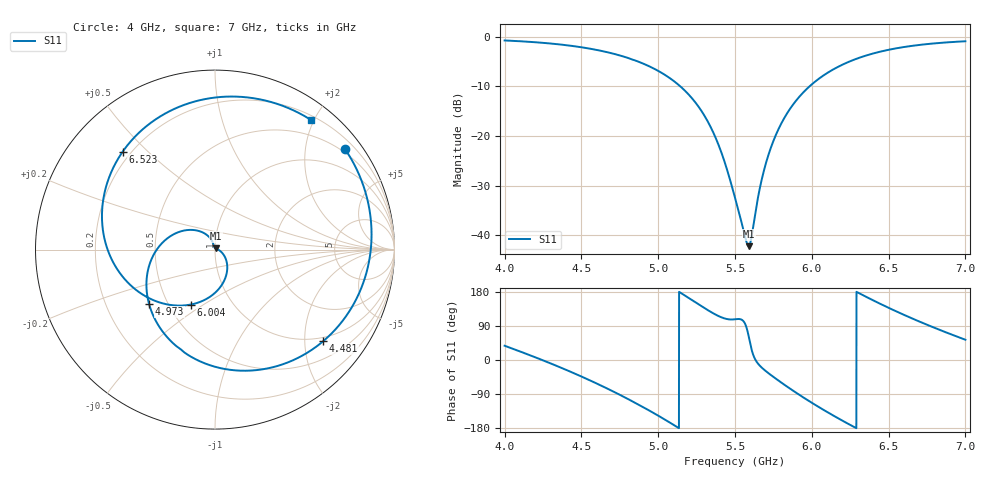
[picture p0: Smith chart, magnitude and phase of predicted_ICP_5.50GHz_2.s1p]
! ICP-predicted S11, target max centred GHz at -10 dB. Complex ensemble mean (passive and causal);
! its |S11| can differ slightly from the dB-domain mean reported in designs.csv.
!  Air_gap = 2.8mm
!  W_Patch = 14.88mm
!  L_Patch = 17.96mm
!  Sx = 1.87mm
!  Sy = 1.72mm
!  W_Patch1 = 14.64mm
!  WS = 1.06mm
!  Curve_Amp1 = 0.78mm
!  Extra = 0.53mm
# GHz S MA R 50
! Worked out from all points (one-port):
!   3001 points, 4 GHz to 7 GHz, reference 50 ohm
!   lowest |S11| = -42.2 dB at 5.589 GHz (marker M1), VSWR 1.02, Z = 50.4 + j0.696 ohm
!   |S11| at or under -10 dB: 5.144 GHz to 5.986 GHz (841.9 MHz wide, 15.1 % of centre)
!   S11 on the Smith chart (normalised r, x): 4 GHz: 0.42, +2.88; 4.481 GHz: 0.90, -2.45; 4.973 GHz: 0.39, -0.31; 6.004 GHz: 0.64, -0.44; 6.523 GHz: 0.17, +0.42; 7 GHz: 0.26, +1.96
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4  0.9156 37.6
4.195  0.8797 7.9
4.375  0.8296 -21.6
4.481  0.7901 -40.1
4.619  0.7249 -65.8
4.75  0.647 -91.8
4.871  0.5601 -117.5
4.973  0.4761 -140.5
5.125  0.3346 -177.4
5.23  0.2297 155.5
5.339  0.1253 127.7
5.419  0.06316 111.5
5.5  0.02392 107.5
5.57  0.009123 91.4
5.589  0.00778 62.6
5.607  0.009522 29.2
5.669  0.0337 -18.1
5.716  0.0633 -34.2
5.787  0.1206 -55.4
5.875  0.2042 -80.2
6.004  0.335 -113.9
6.124  0.4532 -142.9
6.25  0.5657 -171.3
6.385  0.6675 160.3
6.523  0.7497 133.4
6.625  0.797 114.7
6.805  0.8575 84.0
7  0.8988 53.5
